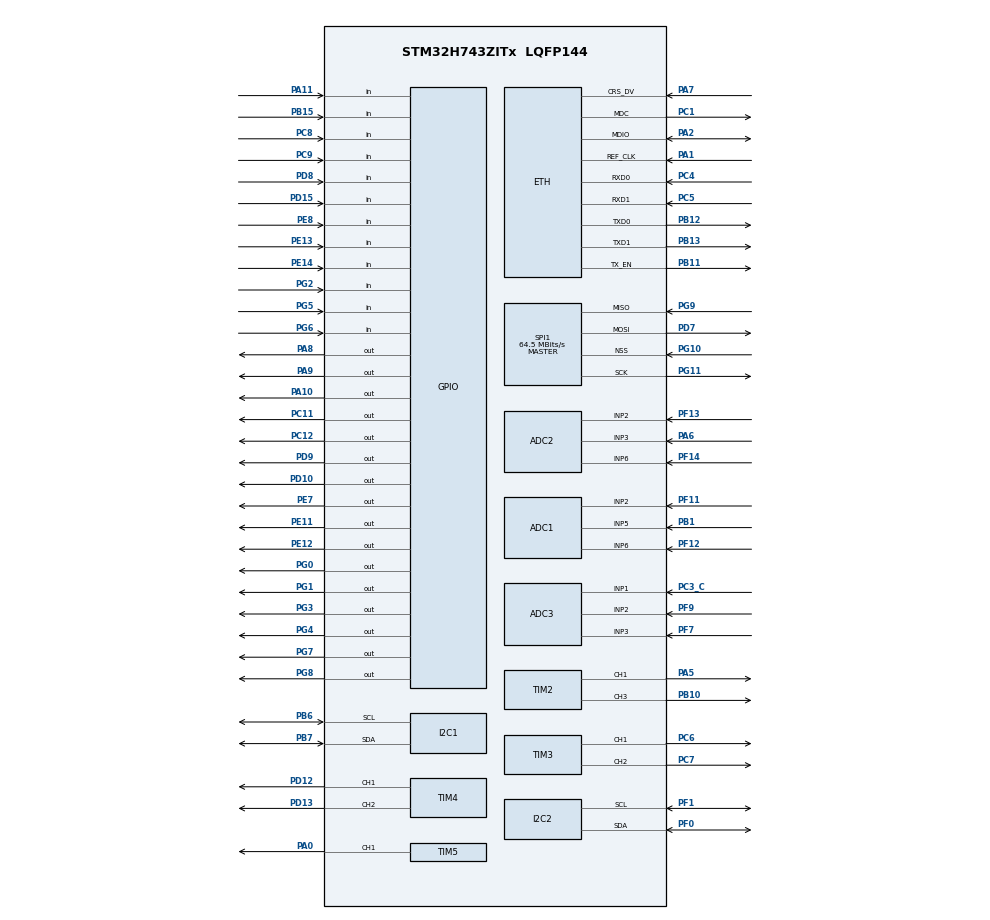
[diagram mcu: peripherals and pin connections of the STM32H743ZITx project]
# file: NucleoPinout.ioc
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ADC1.Channel-0\#ChannelRegularConversion=ADC_CHANNEL_2
ADC1.NbrOfConversionFlag=1
ADC1.OffsetNumber-0\#ChannelRegularConversion=ADC_OFFSET_NONE
ADC1.Rank-0\#ChannelRegularConversion=1
ADC1.SamplingTime-0\#ChannelRegularConversion=ADC_SAMPLETIME_1CYCLE_5
ADC1.master=1
ADC2.Channel-0\#ChannelRegularConversion=ADC_CHANNEL_2
ADC2.NbrOfConversionFlag=1
ADC2.OffsetNumber-0\#ChannelRegularConversion=ADC_OFFSET_NONE
ADC2.Rank-0\#ChannelRegularConversion=1
ADC2.SamplingTime-0\#ChannelRegularConversion=ADC_SAMPLETIME_1CYCLE_5
ADC3.Channel-0\#ChannelRegularConversion=ADC_CHANNEL_1
ADC3.NbrOfConversionFlag=1
ADC3.OffsetNumber-0\#ChannelRegularConversion=ADC_OFFSET_NONE
ADC3.Rank-0\#ChannelRegularConversion=1
ADC3.SamplingTime-0\#ChannelRegularConversion=ADC_SAMPLETIME_1CYCLE_5
ETH.MediaInterface=HAL_ETH_RMII_MODE
Mcu.Family=STM32H7
Mcu.Name=STM32H743ZITx
Mcu.Package=LQFP144
NVIC.PriorityGroup=NVIC_PRIORITYGROUP_4
PA0.Signal=S_TIM5_CH1
PA1.Mode=RMII
PA1.Signal=ETH_REF_CLK
PA10.Signal=GPIO_Output
PA11.Signal=GPIO_Input
PA13\ (JTMS/SWDIO).Mode=JTAG_4_pins
PA13\ (JTMS/SWDIO).Signal=DEBUG_JTMS-SWDIO
PA14\ (JTCK/SWCLK).Mode=JTAG_4_pins
PA14\ (JTCK/SWCLK).Signal=DEBUG_JTCK-SWCLK
PA15\ (JTDI).Mode=JTAG_4_pins
PA15\ (JTDI).Signal=DEBUG_JTDI
PA2.Mode=RMII
PA2.Signal=ETH_MDIO
PA5.Signal=S_TIM2_CH1
PA6.Signal=ADCx_INP3
PA7.Mode=RMII
PA7.Signal=ETH_CRS_DV
PA8.Signal=GPIO_Output
PA9.Signal=GPIO_Output
PB1.Signal=ADCx_INP5
PB10.Signal=S_TIM2_CH3
PB11.Mode=RMII
PB11.Signal=ETH_TX_EN
PB12.Mode=RMII
PB12.Signal=ETH_TXD0
PB13.Mode=RMII
PB13.Signal=ETH_TXD1
PB15.Signal=GPIO_Input
PB3\ (JTDO/TRACESWO).Mode=JTAG_4_pins
PB3\ (JTDO/TRACESWO).Signal=DEBUG_JTDO-SWO
PB6.Mode=I2C
PB6.Signal=I2C1_SCL
PB7.Mode=I2C
PB7.Signal=I2C1_SDA
PC1.Mode=RMII
PC1.Signal=ETH_MDC
PC11.Signal=GPIO_Output
PC12.Signal=GPIO_Output
PC14-OSC32_IN\ (OSC32_IN).Mode=LSE-External-Oscillator
PC14-OSC32_IN\ (OSC32_IN).Signal=RCC_OSC32_IN
PC15-OSC32_OUT\ (OSC32_OUT).Mode=LSE-External-Oscillator
PC15-OSC32_OUT\ (OSC32_OUT).Signal=RCC_OSC32_OUT
PC3_C.Mode=IN1-Single-Ended
PC3_C.Signal=ADC3_INP1
PC4.Mode=RMII
PC4.Signal=ETH_RXD0
PC5.Mode=RMII
PC5.Signal=ETH_RXD1
PC6.Signal=S_TIM3_CH1
PC7.Signal=S_TIM3_CH2
PC8.Signal=GPIO_Input
PC9.Signal=GPIO_Input
PD10.Signal=GPIO_Output
PD12.Signal=S_TIM4_CH1
PD13.Signal=S_TIM4_CH2
PD15.Signal=GPIO_Input
PD7.Mode=Full_Duplex_Master
PD7.Signal=SPI1_MOSI
PD8.Signal=GPIO_Input
PD9.Signal=GPIO_Output
PE11.Signal=GPIO_Output
PE12.Signal=GPIO_Output
PE13.Signal=GPIO_Input
PE14.Signal=GPIO_Input
PE7.Signal=GPIO_Output
PE8.Signal=GPIO_Input
PF0.Mode=I2C
PF0.Signal=I2C2_SDA
PF1.Mode=I2C
PF1.Signal=I2C2_SCL
PF11.Mode=IN2-Single-Ended
PF11.Signal=ADC1_INP2
PF12.Mode=IN6-Single-Ended
PF12.Signal=ADC1_INP6
PF13.Mode=IN2-Single-Ended
PF13.Signal=ADC2_INP2
PF14.Mode=IN6-Single-Ended
PF14.Signal=ADC2_INP6
PF7.Mode=IN3-Single-Ended
PF7.Signal=ADC3_INP3
PF9.Mode=IN2-Single-Ended
PF9.Signal=ADC3_INP2
PG0.Signal=GPIO_Output
PG1.Signal=GPIO_Output
PG10.Mode=NSS_Signal_Hard_Input
PG10.Signal=SPI1_NSS
PG11.Mode=Full_Duplex_Master
PG11.Signal=SPI1_SCK
PG2.Signal=GPIO_Input
PG3.Signal=GPIO_Output
PG4.Signal=GPIO_Output
PG5.Signal=GPIO_Input
PG6.Signal=GPIO_Input
PG7.Signal=GPIO_Output
PG8.Signal=GPIO_Output
PG9.Mode=Full_Duplex_Master
PG9.Signal=SPI1_MISO
PH0-OSC_IN\ (PH0).Mode=HSE-External-Oscillator
PH0-OSC_IN\ (PH0).Signal=RCC_OSC_IN
PH1-OSC_OUT\ (PH1).Mode=HSE-External-Oscillator
PH1-OSC_OUT\ (PH1).Signal=RCC_OSC_OUT
ProjectManager.HeapSize=0x200
ProjectManager.StackSize=0x400
ProjectManager.TargetToolchain=STM32CubeIDE
RCC.ADCFreq_Value=129000000
RCC.APB1Freq_Value=64000000
RCC.APB2Freq_Value=64000000
RCC.APB3Freq_Value=64000000
RCC.APB4Freq_Value=64000000
RCC.CortexFreq_Value=64000000
RCC.HCLKFreq_Value=64000000
RCC.SYSCLKFreq_VALUE=64000000
RCC.USBFreq_Value=129000000
SH.ADCx_INP3.0=ADC2_INP3,IN3-Single-Ended
SH.ADCx_INP5.0=ADC1_INP5,IN5-Single-Ended
SH.S_TIM2_CH1.0=TIM2_CH1,PWM Generation1 CH1
SH.S_TIM2_CH3.0=TIM2_CH3,PWM Generation3 CH3
SH.S_TIM3_CH1.0=TIM3_CH1,PWM Generation1 CH1
SH.S_TIM3_CH2.0=TIM3_CH2,PWM Generation2 CH2
SH.S_TIM4_CH1.0=TIM4_CH1,PWM Generation1 CH1
SH.S_TIM4_CH2.0=TIM4_CH2,PWM Generation2 CH2
SH.S_TIM5_CH1.0=TIM5_CH1,PWM Generation1 CH1
SPI1.CalculateBaudRate=64.5 MBits/s
SPI1.Direction=SPI_DIRECTION_2LINES
SPI1.Mode=SPI_MODE_MASTER
SPI1.VirtualNSS=VM_NSSHARD
SPI1.VirtualType=VM_MASTER
TIM2.Channel-PWM\ Generation1\ CH1=TIM_CHANNEL_1
TIM2.Channel-PWM\ Generation3\ CH3=TIM_CHANNEL_3
TIM3.Channel-PWM\ Generation1\ CH1=TIM_CHANNEL_1
TIM3.Channel-PWM\ Generation2\ CH2=TIM_CHANNEL_2
TIM4.Channel-PWM\ Generation1\ CH1=TIM_CHANNEL_1
TIM4.Channel-PWM\ Generation2\ CH2=TIM_CHANNEL_2
TIM5.Channel-PWM\ Generation1\ CH1=TIM_CHANNEL_1
VP_TIM2_VS_ClockSourceINT.Mode=Internal
VP_TIM3_VS_ClockSourceINT.Mode=Internal
VP_TIM4_VS_ClockSourceINT.Mode=Internal
VP_TIM5_VS_ClockSourceINT.Mode=Internal
board=custom

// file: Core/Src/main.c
/* USER CODE BEGIN Header */
/**
  ******************************************************************************
  * @file           : main.c
  * @brief          : Main program body
  ******************************************************************************
  * @attention
  *
  * <h2><center>&copy; Copyright (c) 2020 STMicroelectronics.
  * All rights reserved.</center></h2>
  *
  * This software component is licensed by ST under BSD 3-Clause license,
  * the "License"; You may not use this file except in compliance with the
  * License. You may obtain a copy of the License at:
  *                        opensource.org/licenses/BSD-3-Clause
  *
  ******************************************************************************
  */
/* USER CODE END Header */

#include "main.h"
#include "string.h"

#if defined ( __ICCARM__ ) /*!< IAR Compiler */

#pragma location=0x30040000
ETH_DMADescTypeDef  DMARxDscrTab[ETH_RX_DESC_CNT]; /* Ethernet Rx DMA Descriptors */
#pragma location=0x30040060
ETH_DMADescTypeDef  DMATxDscrTab[ETH_TX_DESC_CNT]; /* Ethernet Tx DMA Descriptors */
#pragma location=0x30040200
uint8_t Rx_Buff[ETH_RX_DESC_CNT][ETH_MAX_PACKET_SIZE]; /* Ethernet Receive Buffers */

#elif defined ( __CC_ARM )  /* MDK ARM Compiler */

__attribute__((at(0x30040000))) ETH_DMADescTypeDef  DMARxDscrTab[ETH_RX_DESC_CNT]; /* Ethernet Rx DMA Descriptors */
__attribute__((at(0x30040060))) ETH_DMADescTypeDef  DMATxDscrTab[ETH_TX_DESC_CNT]; /* Ethernet Tx DMA Descriptors */
__attribute__((at(0x30040200))) uint8_t Rx_Buff[ETH_RX_DESC_CNT][ETH_MAX_PACKET_SIZE]; /* Ethernet Receive Buffer */

#elif defined ( __GNUC__ ) /* GNU Compiler */

ETH_DMADescTypeDef DMARxDscrTab[ETH_RX_DESC_CNT] __attribute__((section(".RxDecripSection"))); /* Ethernet Rx DMA Descriptors */
ETH_DMADescTypeDef DMATxDscrTab[ETH_TX_DESC_CNT] __attribute__((section(".TxDecripSection")));   /* Ethernet Tx DMA Descriptors */
uint8_t Rx_Buff[ETH_RX_DESC_CNT][ETH_MAX_PACKET_SIZE] __attribute__((section(".RxArraySection"))); /* Ethernet Receive Buffers */

#endif

ETH_TxPacketConfig TxConfig;
ADC_HandleTypeDef hadc1;
ADC_HandleTypeDef hadc2;
ADC_HandleTypeDef hadc3;

ETH_HandleTypeDef heth;

I2C_HandleTypeDef hi2c1;
I2C_HandleTypeDef hi2c2;

SPI_HandleTypeDef hspi1;

TIM_HandleTypeDef htim2;
TIM_HandleTypeDef htim3;
TIM_HandleTypeDef htim4;
TIM_HandleTypeDef htim5;

void SystemClock_Config(void);
static void MX_GPIO_Init(void);
static void MX_ADC1_Init(void);
static void MX_ADC2_Init(void);
static void MX_ADC3_Init(void);
static void MX_ETH_Init(void);
static void MX_I2C1_Init(void);
static void MX_I2C2_Init(void);
static void MX_SPI1_Init(void);
static void MX_TIM2_Init(void);
static void MX_TIM3_Init(void);
static void MX_TIM4_Init(void);
static void MX_TIM5_Init(void);

/* USER CODE BEGIN 0 */
#define SYSCLOCK 64000000 // System Clock is 64MHz
/* USER CODE END 0 */

int main(void)
{

  /* Enable I-Cache---------------------------------------------------------*/
  SCB_EnableICache();

  /* Enable D-Cache---------------------------------------------------------*/
  SCB_EnableDCache();

  /* MCU Configuration--------------------------------------------------------*/

  /* Reset of all peripherals, Initializes the Flash interface and the Systick. */
  HAL_Init();

  /* Configure the system clock */
  SystemClock_Config();

  /* Initialize all configured peripherals */
  MX_GPIO_Init();
  MX_ADC1_Init();
  MX_ADC2_Init();
  MX_ADC3_Init();
  MX_ETH_Init();
  MX_I2C1_Init();
  MX_I2C2_Init();
  MX_SPI1_Init();
  MX_TIM2_Init();
  MX_TIM3_Init();
  MX_TIM4_Init();
  MX_TIM5_Init();
  /* USER CODE BEGIN 2 */
  // Code to Initialize TIMERS
  // HAL_TIM_PWM_Init(&htim2);
  //if (HAL_TIM_PWM_ConfigChannel(&htim2, &sConfigOC, TIM_CHANNEL_1) != HAL_OK)
  //  {
  //    Error_Handler();
  //  }
  if (HAL_TIM_Base_Start(&htim2) != HAL_OK) {
	  Error_Handler();
  }
  if (HAL_TIM_PWM_Start(&htim2, TIM_CHANNEL_1) != HAL_OK) {
	  // Error Starting PWM
	  Error_Handler();
  }
  if (HAL_TIM_PWM_Start(&htim2, TIM_CHANNEL_3) != HAL_OK) {
  	  // Error Starting PWM
  	  Error_Handler();
  }
  if (HAL_TIM_Base_Start(&htim4) != HAL_OK) {
  	  Error_Handler();
  }
  if (HAL_TIM_PWM_Start(&htim4, TIM_CHANNEL_1) != HAL_OK) {
	  // Error Starting PWM
	  Error_Handler();
  }
  if (HAL_TIM_PWM_Start(&htim4, TIM_CHANNEL_2) != HAL_OK) {
	  // Error Starting PWM
	  Error_Handler();
  }
  /* USER CODE END 2 */

  /* Infinite loop */
  while (1)
  {

  }
}

void SystemClock_Config(void)
{
  RCC_OscInitTypeDef RCC_OscInitStruct = {0};
  RCC_ClkInitTypeDef RCC_ClkInitStruct = {0};
  RCC_PeriphCLKInitTypeDef PeriphClkInitStruct = {0};

  /** Supply configuration update enable
  */
  HAL_PWREx_ConfigSupply(PWR_LDO_SUPPLY);
  /** Configure the main internal regulator output voltage
  */
  __HAL_PWR_VOLTAGESCALING_CONFIG(PWR_REGULATOR_VOLTAGE_SCALE3);

  while(!__HAL_PWR_GET_FLAG(PWR_FLAG_VOSRDY)) {}
  /** Macro to configure the PLL clock source
  */
  __HAL_RCC_PLL_PLLSOURCE_CONFIG(RCC_PLLSOURCE_HSI);
  /** Initializes the CPU, AHB and APB busses clocks
  */
  RCC_OscInitStruct.OscillatorType = RCC_OSCILLATORTYPE_HSI;
  RCC_OscInitStruct.HSIState = RCC_HSI_DIV1;
  RCC_OscInitStruct.HSICalibrationValue = RCC_HSICALIBRATION_DEFAULT;
  RCC_OscInitStruct.PLL.PLLState = RCC_PLL_ON;
  RCC_OscInitStruct.PLL.PLLSource = RCC_PLLSOURCE_HSI;
  RCC_OscInitStruct.PLL.PLLM = 32;
  RCC_OscInitStruct.PLL.PLLN = 129;
  RCC_OscInitStruct.PLL.PLLP = 2;
  RCC_OscInitStruct.PLL.PLLQ = 2;
  RCC_OscInitStruct.PLL.PLLR = 2;
  RCC_OscInitStruct.PLL.PLLRGE = RCC_PLL1VCIRANGE_1;
  RCC_OscInitStruct.PLL.PLLVCOSEL = RCC_PLL1VCOWIDE;
  RCC_OscInitStruct.PLL.PLLFRACN = 0;
  if (HAL_RCC_OscConfig(&RCC_OscInitStruct) != HAL_OK)
  {
    Error_Handler();
  }
  /** Initializes the CPU, AHB and APB busses clocks
  */
  RCC_ClkInitStruct.ClockType = RCC_CLOCKTYPE_HCLK|RCC_CLOCKTYPE_SYSCLK
                              |RCC_CLOCKTYPE_PCLK1|RCC_CLOCKTYPE_PCLK2
                              |RCC_CLOCKTYPE_D3PCLK1|RCC_CLOCKTYPE_D1PCLK1;
  RCC_ClkInitStruct.SYSCLKSource = RCC_SYSCLKSOURCE_HSI;
  RCC_ClkInitStruct.SYSCLKDivider = RCC_SYSCLK_DIV1;
  RCC_ClkInitStruct.AHBCLKDivider = RCC_HCLK_DIV1;
  RCC_ClkInitStruct.APB3CLKDivider = RCC_APB3_DIV1;
  RCC_ClkInitStruct.APB1CLKDivider = RCC_APB1_DIV1;
  RCC_ClkInitStruct.APB2CLKDivider = RCC_APB2_DIV1;
  RCC_ClkInitStruct.APB4CLKDivider = RCC_APB4_DIV1;

  if (HAL_RCC_ClockConfig(&RCC_ClkInitStruct, FLASH_LATENCY_0) != HAL_OK)
  {
    Error_Handler();
  }
  PeriphClkInitStruct.PeriphClockSelection = RCC_PERIPHCLK_SPI1|RCC_PERIPHCLK_I2C2
                              |RCC_PERIPHCLK_ADC|RCC_PERIPHCLK_I2C1;
  PeriphClkInitStruct.PLL2.PLL2M = 32;
  PeriphClkInitStruct.PLL2.PLL2N = 129;
  PeriphClkInitStruct.PLL2.PLL2P = 2;
  PeriphClkInitStruct.PLL2.PLL2Q = 2;
  PeriphClkInitStruct.PLL2.PLL2R = 2;
  PeriphClkInitStruct.PLL2.PLL2RGE = RCC_PLL2VCIRANGE_1;
  PeriphClkInitStruct.PLL2.PLL2VCOSEL = RCC_PLL2VCOWIDE;
  PeriphClkInitStruct.PLL2.PLL2FRACN = 0;
  PeriphClkInitStruct.Spi123ClockSelection = RCC_SPI123CLKSOURCE_PLL;
  PeriphClkInitStruct.I2c123ClockSelection = RCC_I2C123CLKSOURCE_D2PCLK1;
  PeriphClkInitStruct.AdcClockSelection = RCC_ADCCLKSOURCE_PLL2;
  if (HAL_RCCEx_PeriphCLKConfig(&PeriphClkInitStruct) != HAL_OK)
  {
    Error_Handler();
  }
}

static void MX_ADC1_Init(void)
{

  ADC_MultiModeTypeDef multimode = {0};
  ADC_ChannelConfTypeDef sConfig = {0};

  /** Common config
  */
  hadc1.Instance = ADC1;
  hadc1.Init.ClockPrescaler = ADC_CLOCK_ASYNC_DIV1;
  hadc1.Init.Resolution = ADC_RESOLUTION_16B;
  hadc1.Init.ScanConvMode = ADC_SCAN_DISABLE;
  hadc1.Init.EOCSelection = ADC_EOC_SINGLE_CONV;
  hadc1.Init.LowPowerAutoWait = DISABLE;
  hadc1.Init.ContinuousConvMode = DISABLE;
  hadc1.Init.NbrOfConversion = 1;
  hadc1.Init.DiscontinuousConvMode = DISABLE;
  hadc1.Init.ExternalTrigConv = ADC_SOFTWARE_START;
  hadc1.Init.ExternalTrigConvEdge = ADC_EXTERNALTRIGCONVEDGE_NONE;
  hadc1.Init.ConversionDataManagement = ADC_CONVERSIONDATA_DR;
  hadc1.Init.Overrun = ADC_OVR_DATA_PRESERVED;
  hadc1.Init.LeftBitShift = ADC_LEFTBITSHIFT_NONE;
  hadc1.Init.OversamplingMode = DISABLE;
  if (HAL_ADC_Init(&hadc1) != HAL_OK)
  {
    Error_Handler();
  }
  /** Configure the ADC multi-mode
  */
  multimode.Mode = ADC_MODE_INDEPENDENT;
  if (HAL_ADCEx_MultiModeConfigChannel(&hadc1, &multimode) != HAL_OK)
  {
    Error_Handler();
  }
  /** Configure Regular Channel
  */
  sConfig.Channel = ADC_CHANNEL_2;
  sConfig.Rank = ADC_REGULAR_RANK_1;
  sConfig.SamplingTime = ADC_SAMPLETIME_1CYCLE_5;
  sConfig.SingleDiff = ADC_SINGLE_ENDED;
  sConfig.OffsetNumber = ADC_OFFSET_NONE;
  sConfig.Offset = 0;
  if (HAL_ADC_ConfigChannel(&hadc1, &sConfig) != HAL_OK)
  {
    Error_Handler();
  }

}

static void MX_ADC2_Init(void)
{

  ADC_ChannelConfTypeDef sConfig = {0};

  /** Common config
  */
  hadc2.Instance = ADC2;
  hadc2.Init.ClockPrescaler = ADC_CLOCK_ASYNC_DIV1;
  hadc2.Init.Resolution = ADC_RESOLUTION_16B;
  hadc2.Init.ScanConvMode = ADC_SCAN_DISABLE;
  hadc2.Init.EOCSelection = ADC_EOC_SINGLE_CONV;
  hadc2.Init.LowPowerAutoWait = DISABLE;
  hadc2.Init.ContinuousConvMode = DISABLE;
  hadc2.Init.NbrOfConversion = 1;
  hadc2.Init.DiscontinuousConvMode = DISABLE;
  hadc2.Init.ExternalTrigConv = ADC_SOFTWARE_START;
  hadc2.Init.ExternalTrigConvEdge = ADC_EXTERNALTRIGCONVEDGE_NONE;
  hadc2.Init.ConversionDataManagement = ADC_CONVERSIONDATA_DR;
  hadc2.Init.Overrun = ADC_OVR_DATA_PRESERVED;
  hadc2.Init.LeftBitShift = ADC_LEFTBITSHIFT_NONE;
  hadc2.Init.OversamplingMode = DISABLE;
  if (HAL_ADC_Init(&hadc2) != HAL_OK)
  {
    Error_Handler();
  }
  /** Configure Regular Channel
  */
  sConfig.Channel = ADC_CHANNEL_2;
  sConfig.Rank = ADC_REGULAR_RANK_1;
  sConfig.SamplingTime = ADC_SAMPLETIME_1CYCLE_5;
  sConfig.SingleDiff = ADC_SINGLE_ENDED;
  sConfig.OffsetNumber = ADC_OFFSET_NONE;
  sConfig.Offset = 0;
  if (HAL_ADC_ConfigChannel(&hadc2, &sConfig) != HAL_OK)
  {
    Error_Handler();
  }

}

static void MX_ADC3_Init(void)
{

  ADC_ChannelConfTypeDef sConfig = {0};

  /** Common config
  */
  hadc3.Instance = ADC3;
  hadc3.Init.ClockPrescaler = ADC_CLOCK_ASYNC_DIV1;
  hadc3.Init.Resolution = ADC_RESOLUTION_16B;
  hadc3.Init.ScanConvMode = ADC_SCAN_DISABLE;
  hadc3.Init.EOCSelection = ADC_EOC_SINGLE_CONV;
  hadc3.Init.LowPowerAutoWait = DISABLE;
  hadc3.Init.ContinuousConvMode = DISABLE;
  hadc3.Init.NbrOfConversion = 1;
  hadc3.Init.DiscontinuousConvMode = DISABLE;
  hadc3.Init.ExternalTrigConv = ADC_SOFTWARE_START;
  hadc3.Init.ExternalTrigConvEdge = ADC_EXTERNALTRIGCONVEDGE_NONE;
  hadc3.Init.ConversionDataManagement = ADC_CONVERSIONDATA_DR;
  hadc3.Init.Overrun = ADC_OVR_DATA_PRESERVED;
  hadc3.Init.LeftBitShift = ADC_LEFTBITSHIFT_NONE;
  hadc3.Init.OversamplingMode = DISABLE;
  if (HAL_ADC_Init(&hadc3) != HAL_OK)
  {
    Error_Handler();
  }
  /** Configure Regular Channel
  */
  sConfig.Channel = ADC_CHANNEL_1;
  sConfig.Rank = ADC_REGULAR_RANK_1;
  sConfig.SamplingTime = ADC_SAMPLETIME_1CYCLE_5;
  sConfig.SingleDiff = ADC_SINGLE_ENDED;
  sConfig.OffsetNumber = ADC_OFFSET_NONE;
  sConfig.Offset = 0;
  if (HAL_ADC_ConfigChannel(&hadc3, &sConfig) != HAL_OK)
  {
    Error_Handler();
  }

}

static void MX_ETH_Init(void)
{

  heth.Instance = ETH;
  heth.Init.MACAddr[0] =   0x00;
  heth.Init.MACAddr[1] =   0x80;
  heth.Init.MACAddr[2] =   0xE1;
  heth.Init.MACAddr[3] =   0x00;
  heth.Init.MACAddr[4] =   0x00;
  heth.Init.MACAddr[5] =   0x00;
  heth.Init.MediaInterface = HAL_ETH_RMII_MODE;
  heth.Init.TxDesc = DMATxDscrTab;
  heth.Init.RxDesc = DMARxDscrTab;
  heth.Init.RxBuffLen = 1524;

  if (HAL_ETH_Init(&heth) != HAL_OK)
  {
    Error_Handler();
  }

  memset(&TxConfig, 0 , sizeof(ETH_TxPacketConfig));
  TxConfig.Attributes = ETH_TX_PACKETS_FEATURES_CSUM | ETH_TX_PACKETS_FEATURES_CRCPAD;
  TxConfig.ChecksumCtrl = ETH_CHECKSUM_IPHDR_PAYLOAD_INSERT_PHDR_CALC;
  TxConfig.CRCPadCtrl = ETH_CRC_PAD_INSERT;

}

static void MX_I2C1_Init(void)
{

  hi2c1.Instance = I2C1;
  hi2c1.Init.Timing = 0x10707DBC;
  hi2c1.Init.OwnAddress1 = 0;
  hi2c1.Init.AddressingMode = I2C_ADDRESSINGMODE_7BIT;
  hi2c1.Init.DualAddressMode = I2C_DUALADDRESS_DISABLE;
  hi2c1.Init.OwnAddress2 = 0;
  hi2c1.Init.OwnAddress2Masks = I2C_OA2_NOMASK;
  hi2c1.Init.GeneralCallMode = I2C_GENERALCALL_DISABLE;
  hi2c1.Init.NoStretchMode = I2C_NOSTRETCH_DISABLE;
  if (HAL_I2C_Init(&hi2c1) != HAL_OK)
  {
    Error_Handler();
  }
  /** Configure Analogue filter
  */
  if (HAL_I2CEx_ConfigAnalogFilter(&hi2c1, I2C_ANALOGFILTER_ENABLE) != HAL_OK)
  {
    Error_Handler();
  }
  /** Configure Digital filter
  */
  if (HAL_I2CEx_ConfigDigitalFilter(&hi2c1, 0) != HAL_OK)
  {
    Error_Handler();
  }

}

static void MX_I2C2_Init(void)
{

  hi2c2.Instance = I2C2;
  hi2c2.Init.Timing = 0x10707DBC;
  hi2c2.Init.OwnAddress1 = 0;
  hi2c2.Init.AddressingMode = I2C_ADDRESSINGMODE_7BIT;
  hi2c2.Init.DualAddressMode = I2C_DUALADDRESS_DISABLE;
  hi2c2.Init.OwnAddress2 = 0;
  hi2c2.Init.OwnAddress2Masks = I2C_OA2_NOMASK;
  hi2c2.Init.GeneralCallMode = I2C_GENERALCALL_DISABLE;
  hi2c2.Init.NoStretchMode = I2C_NOSTRETCH_DISABLE;
  if (HAL_I2C_Init(&hi2c2) != HAL_OK)
  {
    Error_Handler();
  }
  /** Configure Analogue filter
  */
  if (HAL_I2CEx_ConfigAnalogFilter(&hi2c2, I2C_ANALOGFILTER_ENABLE) != HAL_OK)
  {
    Error_Handler();
  }
  /** Configure Digital filter
  */
  if (HAL_I2CEx_ConfigDigitalFilter(&hi2c2, 0) != HAL_OK)
  {
    Error_Handler();
  }

}

static void MX_SPI1_Init(void)
{

  /* SPI1 parameter configuration*/
  hspi1.Instance = SPI1;
  hspi1.Init.Mode = SPI_MODE_MASTER;
  hspi1.Init.Direction = SPI_DIRECTION_2LINES;
  hspi1.Init.DataSize = SPI_DATASIZE_4BIT;
  hspi1.Init.CLKPolarity = SPI_POLARITY_LOW;
  hspi1.Init.CLKPhase = SPI_PHASE_1EDGE;
  hspi1.Init.NSS = SPI_NSS_HARD_INPUT;
  hspi1.Init.BaudRatePrescaler = SPI_BAUDRATEPRESCALER_2;
  hspi1.Init.FirstBit = SPI_FIRSTBIT_MSB;
  hspi1.Init.TIMode = SPI_TIMODE_DISABLE;
  hspi1.Init.CRCCalculation = SPI_CRCCALCULATION_DISABLE;
  hspi1.Init.CRCPolynomial = 0x0;
  hspi1.Init.NSSPMode = SPI_NSS_PULSE_ENABLE;
  hspi1.Init.NSSPolarity = SPI_NSS_POLARITY_LOW;
  hspi1.Init.FifoThreshold = SPI_FIFO_THRESHOLD_01DATA;
  hspi1.Init.TxCRCInitializationPattern = SPI_CRC_INITIALIZATION_ALL_ZERO_PATTERN;
  hspi1.Init.RxCRCInitializationPattern = SPI_CRC_INITIALIZATION_ALL_ZERO_PATTERN;
  hspi1.Init.MasterSSIdleness = SPI_MASTER_SS_IDLENESS_00CYCLE;
  hspi1.Init.MasterInterDataIdleness = SPI_MASTER_INTERDATA_IDLENESS_00CYCLE;
  hspi1.Init.MasterReceiverAutoSusp = SPI_MASTER_RX_AUTOSUSP_DISABLE;
  hspi1.Init.MasterKeepIOState = SPI_MASTER_KEEP_IO_STATE_DISABLE;
  hspi1.Init.IOSwap = SPI_IO_SWAP_DISABLE;
  if (HAL_SPI_Init(&hspi1) != HAL_OK)
  {
    Error_Handler();
  }

}

static void MX_TIM2_Init(void)
{

  TIM_ClockConfigTypeDef sClockSourceConfig = {0};
  TIM_MasterConfigTypeDef sMasterConfig = {0};
  TIM_OC_InitTypeDef sConfigOC = {0};

  htim2.Instance = TIM2;
  htim2.Init.Prescaler = 2000;
  htim2.Init.CounterMode = TIM_COUNTERMODE_UP;
  htim2.Init.Period = 16000;
  htim2.Init.ClockDivision = TIM_CLOCKDIVISION_DIV1;
  htim2.Init.AutoReloadPreload = TIM_AUTORELOAD_PRELOAD_ENABLE;
  if (HAL_TIM_Base_Init(&htim2) != HAL_OK)
  {
    Error_Handler();
  }
  sClockSourceConfig.ClockSource = TIM_CLOCKSOURCE_INTERNAL;
  if (HAL_TIM_ConfigClockSource(&htim2, &sClockSourceConfig) != HAL_OK)
  {
    Error_Handler();
  }
  if (HAL_TIM_PWM_Init(&htim2) != HAL_OK)
  {
    Error_Handler();
  }
  sMasterConfig.MasterOutputTrigger = TIM_TRGO_RESET;
  sMasterConfig.MasterSlaveMode = TIM_MASTERSLAVEMODE_DISABLE;
  if (HAL_TIMEx_MasterConfigSynchronization(&htim2, &sMasterConfig) != HAL_OK)
  {
    Error_Handler();
  }
  sConfigOC.OCMode = TIM_OCMODE_PWM1;
  sConfigOC.Pulse = 8000;
  sConfigOC.OCPolarity = TIM_OCPOLARITY_HIGH;
  sConfigOC.OCFastMode = TIM_OCFAST_DISABLE;
  if (HAL_TIM_PWM_ConfigChannel(&htim2, &sConfigOC, TIM_CHANNEL_1) != HAL_OK)
  {
    Error_Handler();
  }
  sConfigOC.Pulse = 6000;
  if (HAL_TIM_PWM_ConfigChannel(&htim2, &sConfigOC, TIM_CHANNEL_3) != HAL_OK)
  {
    Error_Handler();
  }
  HAL_TIM_MspPostInit(&htim2);

}

static void MX_TIM3_Init(void)
{

  TIM_ClockConfigTypeDef sClockSourceConfig = {0};
  TIM_MasterConfigTypeDef sMasterConfig = {0};
  TIM_OC_InitTypeDef sConfigOC = {0};

  htim3.Instance = TIM3;
  htim3.Init.Prescaler = 2000;
  htim3.Init.CounterMode = TIM_COUNTERMODE_UP;
  htim3.Init.Period = 32000;
  htim3.Init.ClockDivision = TIM_CLOCKDIVISION_DIV1;
  htim3.Init.AutoReloadPreload = TIM_AUTORELOAD_PRELOAD_DISABLE;
  if (HAL_TIM_Base_Init(&htim3) != HAL_OK)
  {
    Error_Handler();
  }
  sClockSourceConfig.ClockSource = TIM_CLOCKSOURCE_INTERNAL;
  if (HAL_TIM_ConfigClockSource(&htim3, &sClockSourceConfig) != HAL_OK)
  {
    Error_Handler();
  }
  if (HAL_TIM_PWM_Init(&htim3) != HAL_OK)
  {
    Error_Handler();
  }
  sMasterConfig.MasterOutputTrigger = TIM_TRGO_RESET;
  sMasterConfig.MasterSlaveMode = TIM_MASTERSLAVEMODE_DISABLE;
  if (HAL_TIMEx_MasterConfigSynchronization(&htim3, &sMasterConfig) != HAL_OK)
  {
    Error_Handler();
  }
  sConfigOC.OCMode = TIM_OCMODE_PWM1;
  sConfigOC.Pulse = 16000;
  sConfigOC.OCPolarity = TIM_OCPOLARITY_HIGH;
  sConfigOC.OCFastMode = TIM_OCFAST_DISABLE;
  if (HAL_TIM_PWM_ConfigChannel(&htim3, &sConfigOC, TIM_CHANNEL_1) != HAL_OK)
  {
    Error_Handler();
  }
  if (HAL_TIM_PWM_ConfigChannel(&htim3, &sConfigOC, TIM_CHANNEL_2) != HAL_OK)
  {
    Error_Handler();
  }
  HAL_TIM_MspPostInit(&htim3);

}

static void MX_TIM4_Init(void)
{

  TIM_ClockConfigTypeDef sClockSourceConfig = {0};
  TIM_MasterConfigTypeDef sMasterConfig = {0};
  TIM_OC_InitTypeDef sConfigOC = {0};

  htim4.Instance = TIM4;
  htim4.Init.Prescaler = 2000;
  htim4.Init.CounterMode = TIM_COUNTERMODE_UP;
  htim4.Init.Period = 32000;
  htim4.Init.ClockDivision = TIM_CLOCKDIVISION_DIV1;
  htim4.Init.AutoReloadPreload = TIM_AUTORELOAD_PRELOAD_DISABLE;
  if (HAL_TIM_Base_Init(&htim4) != HAL_OK)
  {
    Error_Handler();
  }
  sClockSourceConfig.ClockSource = TIM_CLOCKSOURCE_INTERNAL;
  if (HAL_TIM_ConfigClockSource(&htim4, &sClockSourceConfig) != HAL_OK)
  {
    Error_Handler();
  }
  if (HAL_TIM_PWM_Init(&htim4) != HAL_OK)
  {
    Error_Handler();
  }
  sMasterConfig.MasterOutputTrigger = TIM_TRGO_RESET;
  sMasterConfig.MasterSlaveMode = TIM_MASTERSLAVEMODE_DISABLE;
  if (HAL_TIMEx_MasterConfigSynchronization(&htim4, &sMasterConfig) != HAL_OK)
  {
    Error_Handler();
  }
  sConfigOC.OCMode = TIM_OCMODE_PWM1;
  sConfigOC.Pulse = 16000;
  sConfigOC.OCPolarity = TIM_OCPOLARITY_HIGH;
  sConfigOC.OCFastMode = TIM_OCFAST_DISABLE;
  if (HAL_TIM_PWM_ConfigChannel(&htim4, &sConfigOC, TIM_CHANNEL_1) != HAL_OK)
  {
    Error_Handler();
  }
  sConfigOC.Pulse = 8000;
  if (HAL_TIM_PWM_ConfigChannel(&htim4, &sConfigOC, TIM_CHANNEL_2) != HAL_OK)
  {
    Error_Handler();
  }
  HAL_TIM_MspPostInit(&htim4);

}

static void MX_TIM5_Init(void)
{

  TIM_ClockConfigTypeDef sClockSourceConfig = {0};
  TIM_MasterConfigTypeDef sMasterConfig = {0};
  TIM_OC_InitTypeDef sConfigOC = {0};

  htim5.Instance = TIM5;
  htim5.Init.Prescaler = 0;
  htim5.Init.CounterMode = TIM_COUNTERMODE_UP;
  htim5.Init.Period = 0;
  htim5.Init.ClockDivision = TIM_CLOCKDIVISION_DIV1;
  htim5.Init.AutoReloadPreload = TIM_AUTORELOAD_PRELOAD_DISABLE;
  if (HAL_TIM_Base_Init(&htim5) != HAL_OK)
  {
    Error_Handler();
  }
  sClockSourceConfig.ClockSource = TIM_CLOCKSOURCE_INTERNAL;
  if (HAL_TIM_ConfigClockSource(&htim5, &sClockSourceConfig) != HAL_OK)
  {
    Error_Handler();
  }
  if (HAL_TIM_PWM_Init(&htim5) != HAL_OK)
  {
    Error_Handler();
  }
  sMasterConfig.MasterOutputTrigger = TIM_TRGO_RESET;
  sMasterConfig.MasterSlaveMode = TIM_MASTERSLAVEMODE_DISABLE;
  if (HAL_TIMEx_MasterConfigSynchronization(&htim5, &sMasterConfig) != HAL_OK)
  {
    Error_Handler();
  }
  sConfigOC.OCMode = TIM_OCMODE_PWM1;
  sConfigOC.Pulse = 0;
  sConfigOC.OCPolarity = TIM_OCPOLARITY_HIGH;
  sConfigOC.OCFastMode = TIM_OCFAST_DISABLE;
  if (HAL_TIM_PWM_ConfigChannel(&htim5, &sConfigOC, TIM_CHANNEL_1) != HAL_OK)
  {
    Error_Handler();
  }
  HAL_TIM_MspPostInit(&htim5);

}

static void MX_GPIO_Init(void)
{
  GPIO_InitTypeDef GPIO_InitStruct = {0};

  /* GPIO Ports Clock Enable */
  __HAL_RCC_GPIOC_CLK_ENABLE();
  __HAL_RCC_GPIOF_CLK_ENABLE();
  __HAL_RCC_GPIOH_CLK_ENABLE();
  __HAL_RCC_GPIOA_CLK_ENABLE();
  __HAL_RCC_GPIOB_CLK_ENABLE();
  __HAL_RCC_GPIOG_CLK_ENABLE();
  __HAL_RCC_GPIOE_CLK_ENABLE();
  __HAL_RCC_GPIOD_CLK_ENABLE();

  /*Configure GPIO pin Output Level */
  HAL_GPIO_WritePin(GPIOG, GPIO_PIN_0|GPIO_PIN_1|GPIO_PIN_3|GPIO_PIN_4
                          |GPIO_PIN_7|GPIO_PIN_8, GPIO_PIN_RESET);

  /*Configure GPIO pin Output Level */
  HAL_GPIO_WritePin(GPIOE, GPIO_PIN_7|GPIO_PIN_11|GPIO_PIN_12|GPIO_PIN_1, GPIO_PIN_RESET);

  /*Configure GPIO pin Output Level */
  HAL_GPIO_WritePin(GPIOB, GPIO_PIN_14, GPIO_PIN_RESET);

  /*Configure GPIO pin Output Level */
  HAL_GPIO_WritePin(GPIOD, GPIO_PIN_9|GPIO_PIN_10, GPIO_PIN_RESET);

  /*Configure GPIO pin Output Level */
  HAL_GPIO_WritePin(GPIOA, GPIO_PIN_8|GPIO_PIN_9|GPIO_PIN_10, GPIO_PIN_RESET);

  /*Configure GPIO pin Output Level */
  HAL_GPIO_WritePin(GPIOC, GPIO_PIN_11|GPIO_PIN_12, GPIO_PIN_RESET);

  /*Configure GPIO pins : PG0 PG1 PG3 PG4
                           PG7 PG8 */
  GPIO_InitStruct.Pin = GPIO_PIN_0|GPIO_PIN_1|GPIO_PIN_3|GPIO_PIN_4
                          |GPIO_PIN_7|GPIO_PIN_8;
  GPIO_InitStruct.Mode = GPIO_MODE_OUTPUT_PP;
  GPIO_InitStruct.Pull = GPIO_NOPULL;
  GPIO_InitStruct.Speed = GPIO_SPEED_FREQ_LOW;
  HAL_GPIO_Init(GPIOG, &GPIO_InitStruct);

  /*Configure GPIO pins : PE7 PE11 PE12 PE1 */
  GPIO_InitStruct.Pin = GPIO_PIN_7|GPIO_PIN_11|GPIO_PIN_12|GPIO_PIN_1;
  GPIO_InitStruct.Mode = GPIO_MODE_OUTPUT_PP;
  GPIO_InitStruct.Pull = GPIO_NOPULL;
  GPIO_InitStruct.Speed = GPIO_SPEED_FREQ_LOW;
  HAL_GPIO_Init(GPIOE, &GPIO_InitStruct);

  /*Configure GPIO pins : PE8 PE13 PE14 */
  GPIO_InitStruct.Pin = GPIO_PIN_8|GPIO_PIN_13|GPIO_PIN_14;
  GPIO_InitStruct.Mode = GPIO_MODE_INPUT;
  GPIO_InitStruct.Pull = GPIO_NOPULL;
  HAL_GPIO_Init(GPIOE, &GPIO_InitStruct);

  /*Configure GPIO pin : PB14 */
  GPIO_InitStruct.Pin = GPIO_PIN_14;
  GPIO_InitStruct.Mode = GPIO_MODE_OUTPUT_PP;
  GPIO_InitStruct.Pull = GPIO_NOPULL;
  GPIO_InitStruct.Speed = GPIO_SPEED_FREQ_LOW;
  HAL_GPIO_Init(GPIOB, &GPIO_InitStruct);

  /*Configure GPIO pin : PB15 */
  GPIO_InitStruct.Pin = GPIO_PIN_15;
  GPIO_InitStruct.Mode = GPIO_MODE_INPUT;
  GPIO_InitStruct.Pull = GPIO_NOPULL;
  HAL_GPIO_Init(GPIOB, &GPIO_InitStruct);

  /*Configure GPIO pins : PD8 PD15 */
  GPIO_InitStruct.Pin = GPIO_PIN_8|GPIO_PIN_15;
  GPIO_InitStruct.Mode = GPIO_MODE_INPUT;
  GPIO_InitStruct.Pull = GPIO_NOPULL;
  HAL_GPIO_Init(GPIOD, &GPIO_InitStruct);

  /*Configure GPIO pins : PD9 PD10 */
  GPIO_InitStruct.Pin = GPIO_PIN_9|GPIO_PIN_10;
  GPIO_InitStruct.Mode = GPIO_MODE_OUTPUT_PP;
  GPIO_InitStruct.Pull = GPIO_NOPULL;
  GPIO_InitStruct.Speed = GPIO_SPEED_FREQ_LOW;
  HAL_GPIO_Init(GPIOD, &GPIO_InitStruct);

  /*Configure GPIO pins : PG2 PG5 PG6 */
  GPIO_InitStruct.Pin = GPIO_PIN_2|GPIO_PIN_5|GPIO_PIN_6;
  GPIO_InitStruct.Mode = GPIO_MODE_INPUT;
  GPIO_InitStruct.Pull = GPIO_NOPULL;
  HAL_GPIO_Init(GPIOG, &GPIO_InitStruct);

  /*Configure GPIO pins : PC8 PC9 */
  GPIO_InitStruct.Pin = GPIO_PIN_8|GPIO_PIN_9;
  GPIO_InitStruct.Mode = GPIO_MODE_INPUT;
  GPIO_InitStruct.Pull = GPIO_NOPULL;
  HAL_GPIO_Init(GPIOC, &GPIO_InitStruct);

  /*Configure GPIO pins : PA8 PA9 PA10 */
  GPIO_InitStruct.Pin = GPIO_PIN_8|GPIO_PIN_9|GPIO_PIN_10;
  GPIO_InitStruct.Mode = GPIO_MODE_OUTPUT_PP;
  GPIO_InitStruct.Pull = GPIO_NOPULL;
  GPIO_InitStruct.Speed = GPIO_SPEED_FREQ_LOW;
  HAL_GPIO_Init(GPIOA, &GPIO_InitStruct);

  /*Configure GPIO pin : PA11 */
  GPIO_InitStruct.Pin = GPIO_PIN_11;
  GPIO_InitStruct.Mode = GPIO_MODE_INPUT;
  GPIO_InitStruct.Pull = GPIO_NOPULL;
  HAL_GPIO_Init(GPIOA, &GPIO_InitStruct);

  /*Configure GPIO pins : PC11 PC12 */
  GPIO_InitStruct.Pin = GPIO_PIN_11|GPIO_PIN_12;
  GPIO_InitStruct.Mode = GPIO_MODE_OUTPUT_PP;
  GPIO_InitStruct.Pull = GPIO_NOPULL;
  GPIO_InitStruct.Speed = GPIO_SPEED_FREQ_LOW;
  HAL_GPIO_Init(GPIOC, &GPIO_InitStruct);

}

void Error_Handler(void)
{
}

/************************ (C) COPYRIGHT STMicroelectronics *****END OF FILE****/
